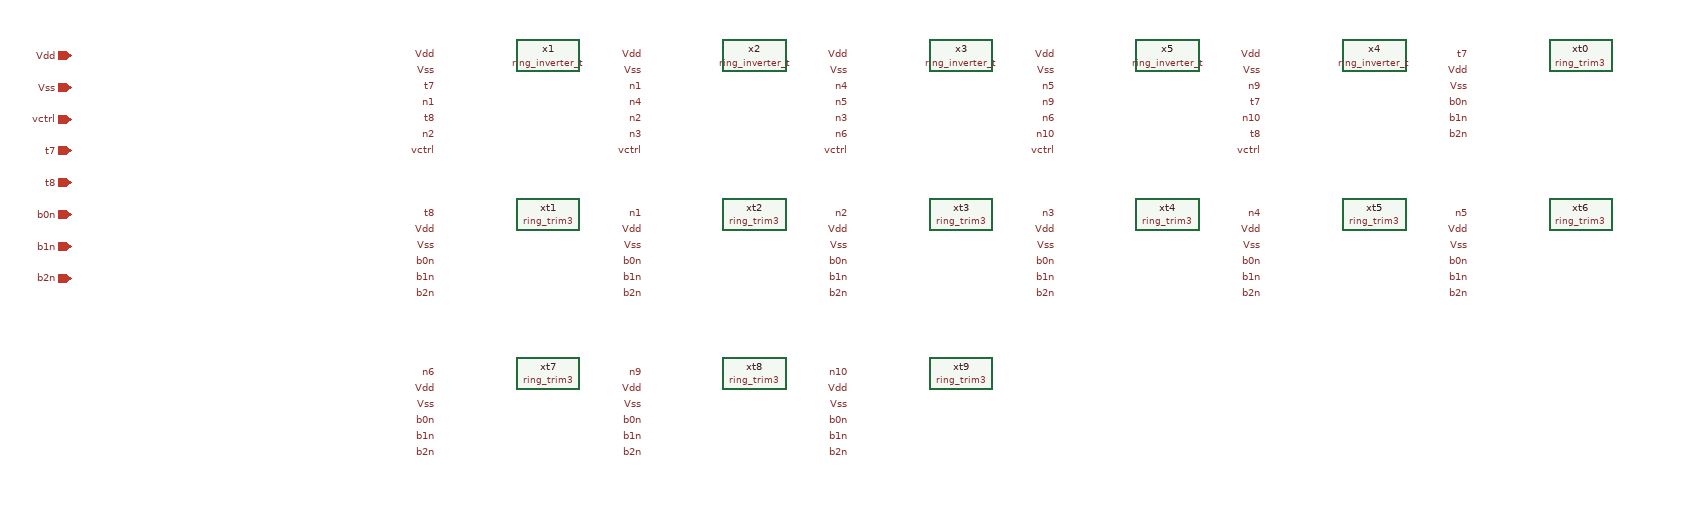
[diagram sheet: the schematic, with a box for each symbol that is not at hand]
v {xschem version=3.4.5 file_version=1.2}
G {}
K {}
V {}
S {}
E {}
C {devices/iopin.sym} -400 0 0 0 {name=p1 lab=Vdd}
C {devices/iopin.sym} -400 40 0 0 {name=p2 lab=Vss}
C {devices/iopin.sym} -400 80 0 0 {name=p3 lab=vctrl}
C {devices/iopin.sym} -400 120 0 0 {name=p4 lab=t7}
C {devices/iopin.sym} -400 160 0 0 {name=p5 lab=t8}
C {devices/iopin.sym} -400 200 0 0 {name=p6 lab=b0n}
C {devices/iopin.sym} -400 240 0 0 {name=p7 lab=b1n}
C {devices/iopin.sym} -400 280 0 0 {name=p8 lab=b2n}
C {devices/lab_pin.sym} 60 0 0 0 {name=l1 sig_type=std_logic lab=Vdd}
C {devices/lab_pin.sym} 60 20 0 0 {name=l2 sig_type=std_logic lab=Vss}
C {devices/lab_pin.sym} 60 40 0 0 {name=l3 sig_type=std_logic lab=t7}
C {devices/lab_pin.sym} 60 60 0 0 {name=l4 sig_type=std_logic lab=n1}
C {devices/lab_pin.sym} 60 80 0 0 {name=l5 sig_type=std_logic lab=t8}
C {devices/lab_pin.sym} 60 100 0 0 {name=l6 sig_type=std_logic lab=n2}
C {devices/lab_pin.sym} 60 120 0 0 {name=l7 sig_type=std_logic lab=vctrl}
C {cml/ring_inverter_t.sym} 200 0 0 0 {name=x1}
C {devices/lab_pin.sym} 320 0 0 0 {name=l8 sig_type=std_logic lab=Vdd}
C {devices/lab_pin.sym} 320 20 0 0 {name=l9 sig_type=std_logic lab=Vss}
C {devices/lab_pin.sym} 320 40 0 0 {name=l10 sig_type=std_logic lab=n1}
C {devices/lab_pin.sym} 320 60 0 0 {name=l11 sig_type=std_logic lab=n4}
C {devices/lab_pin.sym} 320 80 0 0 {name=l12 sig_type=std_logic lab=n2}
C {devices/lab_pin.sym} 320 100 0 0 {name=l13 sig_type=std_logic lab=n3}
C {devices/lab_pin.sym} 320 120 0 0 {name=l14 sig_type=std_logic lab=vctrl}
C {cml/ring_inverter_t.sym} 460 0 0 0 {name=x2}
C {devices/lab_pin.sym} 580 0 0 0 {name=l15 sig_type=std_logic lab=Vdd}
C {devices/lab_pin.sym} 580 20 0 0 {name=l16 sig_type=std_logic lab=Vss}
C {devices/lab_pin.sym} 580 40 0 0 {name=l17 sig_type=std_logic lab=n4}
C {devices/lab_pin.sym} 580 60 0 0 {name=l18 sig_type=std_logic lab=n5}
C {devices/lab_pin.sym} 580 80 0 0 {name=l19 sig_type=std_logic lab=n3}
C {devices/lab_pin.sym} 580 100 0 0 {name=l20 sig_type=std_logic lab=n6}
C {devices/lab_pin.sym} 580 120 0 0 {name=l21 sig_type=std_logic lab=vctrl}
C {cml/ring_inverter_t.sym} 720 0 0 0 {name=x3}
C {devices/lab_pin.sym} 840 0 0 0 {name=l22 sig_type=std_logic lab=Vdd}
C {devices/lab_pin.sym} 840 20 0 0 {name=l23 sig_type=std_logic lab=Vss}
C {devices/lab_pin.sym} 840 40 0 0 {name=l24 sig_type=std_logic lab=n5}
C {devices/lab_pin.sym} 840 60 0 0 {name=l25 sig_type=std_logic lab=n9}
C {devices/lab_pin.sym} 840 80 0 0 {name=l26 sig_type=std_logic lab=n6}
C {devices/lab_pin.sym} 840 100 0 0 {name=l27 sig_type=std_logic lab=n10}
C {devices/lab_pin.sym} 840 120 0 0 {name=l28 sig_type=std_logic lab=vctrl}
C {cml/ring_inverter_t.sym} 980 0 0 0 {name=x5}
C {devices/lab_pin.sym} 1100 0 0 0 {name=l29 sig_type=std_logic lab=Vdd}
C {devices/lab_pin.sym} 1100 20 0 0 {name=l30 sig_type=std_logic lab=Vss}
C {devices/lab_pin.sym} 1100 40 0 0 {name=l31 sig_type=std_logic lab=n9}
C {devices/lab_pin.sym} 1100 60 0 0 {name=l32 sig_type=std_logic lab=t7}
C {devices/lab_pin.sym} 1100 80 0 0 {name=l33 sig_type=std_logic lab=n10}
C {devices/lab_pin.sym} 1100 100 0 0 {name=l34 sig_type=std_logic lab=t8}
C {devices/lab_pin.sym} 1100 120 0 0 {name=l35 sig_type=std_logic lab=vctrl}
C {cml/ring_inverter_t.sym} 1240 0 0 0 {name=x4}
C {devices/lab_pin.sym} 1360 0 0 0 {name=l36 sig_type=std_logic lab=t7}
C {devices/lab_pin.sym} 1360 20 0 0 {name=l37 sig_type=std_logic lab=Vdd}
C {devices/lab_pin.sym} 1360 40 0 0 {name=l38 sig_type=std_logic lab=Vss}
C {devices/lab_pin.sym} 1360 60 0 0 {name=l39 sig_type=std_logic lab=b0n}
C {devices/lab_pin.sym} 1360 80 0 0 {name=l40 sig_type=std_logic lab=b1n}
C {devices/lab_pin.sym} 1360 100 0 0 {name=l41 sig_type=std_logic lab=b2n}
C {cml/ring_trim3.sym} 1500 0 0 0 {name=xt0}
C {devices/lab_pin.sym} 60 200 0 0 {name=l42 sig_type=std_logic lab=t8}
C {devices/lab_pin.sym} 60 220 0 0 {name=l43 sig_type=std_logic lab=Vdd}
C {devices/lab_pin.sym} 60 240 0 0 {name=l44 sig_type=std_logic lab=Vss}
C {devices/lab_pin.sym} 60 260 0 0 {name=l45 sig_type=std_logic lab=b0n}
C {devices/lab_pin.sym} 60 280 0 0 {name=l46 sig_type=std_logic lab=b1n}
C {devices/lab_pin.sym} 60 300 0 0 {name=l47 sig_type=std_logic lab=b2n}
C {cml/ring_trim3.sym} 200 200 0 0 {name=xt1}
C {devices/lab_pin.sym} 320 200 0 0 {name=l48 sig_type=std_logic lab=n1}
C {devices/lab_pin.sym} 320 220 0 0 {name=l49 sig_type=std_logic lab=Vdd}
C {devices/lab_pin.sym} 320 240 0 0 {name=l50 sig_type=std_logic lab=Vss}
C {devices/lab_pin.sym} 320 260 0 0 {name=l51 sig_type=std_logic lab=b0n}
C {devices/lab_pin.sym} 320 280 0 0 {name=l52 sig_type=std_logic lab=b1n}
C {devices/lab_pin.sym} 320 300 0 0 {name=l53 sig_type=std_logic lab=b2n}
C {cml/ring_trim3.sym} 460 200 0 0 {name=xt2}
C {devices/lab_pin.sym} 580 200 0 0 {name=l54 sig_type=std_logic lab=n2}
C {devices/lab_pin.sym} 580 220 0 0 {name=l55 sig_type=std_logic lab=Vdd}
C {devices/lab_pin.sym} 580 240 0 0 {name=l56 sig_type=std_logic lab=Vss}
C {devices/lab_pin.sym} 580 260 0 0 {name=l57 sig_type=std_logic lab=b0n}
C {devices/lab_pin.sym} 580 280 0 0 {name=l58 sig_type=std_logic lab=b1n}
C {devices/lab_pin.sym} 580 300 0 0 {name=l59 sig_type=std_logic lab=b2n}
C {cml/ring_trim3.sym} 720 200 0 0 {name=xt3}
C {devices/lab_pin.sym} 840 200 0 0 {name=l60 sig_type=std_logic lab=n3}
C {devices/lab_pin.sym} 840 220 0 0 {name=l61 sig_type=std_logic lab=Vdd}
C {devices/lab_pin.sym} 840 240 0 0 {name=l62 sig_type=std_logic lab=Vss}
C {devices/lab_pin.sym} 840 260 0 0 {name=l63 sig_type=std_logic lab=b0n}
C {devices/lab_pin.sym} 840 280 0 0 {name=l64 sig_type=std_logic lab=b1n}
C {devices/lab_pin.sym} 840 300 0 0 {name=l65 sig_type=std_logic lab=b2n}
C {cml/ring_trim3.sym} 980 200 0 0 {name=xt4}
C {devices/lab_pin.sym} 1100 200 0 0 {name=l66 sig_type=std_logic lab=n4}
C {devices/lab_pin.sym} 1100 220 0 0 {name=l67 sig_type=std_logic lab=Vdd}
C {devices/lab_pin.sym} 1100 240 0 0 {name=l68 sig_type=std_logic lab=Vss}
C {devices/lab_pin.sym} 1100 260 0 0 {name=l69 sig_type=std_logic lab=b0n}
C {devices/lab_pin.sym} 1100 280 0 0 {name=l70 sig_type=std_logic lab=b1n}
C {devices/lab_pin.sym} 1100 300 0 0 {name=l71 sig_type=std_logic lab=b2n}
C {cml/ring_trim3.sym} 1240 200 0 0 {name=xt5}
C {devices/lab_pin.sym} 1360 200 0 0 {name=l72 sig_type=std_logic lab=n5}
C {devices/lab_pin.sym} 1360 220 0 0 {name=l73 sig_type=std_logic lab=Vdd}
C {devices/lab_pin.sym} 1360 240 0 0 {name=l74 sig_type=std_logic lab=Vss}
C {devices/lab_pin.sym} 1360 260 0 0 {name=l75 sig_type=std_logic lab=b0n}
C {devices/lab_pin.sym} 1360 280 0 0 {name=l76 sig_type=std_logic lab=b1n}
C {devices/lab_pin.sym} 1360 300 0 0 {name=l77 sig_type=std_logic lab=b2n}
C {cml/ring_trim3.sym} 1500 200 0 0 {name=xt6}
C {devices/lab_pin.sym} 60 400 0 0 {name=l78 sig_type=std_logic lab=n6}
C {devices/lab_pin.sym} 60 420 0 0 {name=l79 sig_type=std_logic lab=Vdd}
C {devices/lab_pin.sym} 60 440 0 0 {name=l80 sig_type=std_logic lab=Vss}
C {devices/lab_pin.sym} 60 460 0 0 {name=l81 sig_type=std_logic lab=b0n}
C {devices/lab_pin.sym} 60 480 0 0 {name=l82 sig_type=std_logic lab=b1n}
C {devices/lab_pin.sym} 60 500 0 0 {name=l83 sig_type=std_logic lab=b2n}
C {cml/ring_trim3.sym} 200 400 0 0 {name=xt7}
C {devices/lab_pin.sym} 320 400 0 0 {name=l84 sig_type=std_logic lab=n9}
C {devices/lab_pin.sym} 320 420 0 0 {name=l85 sig_type=std_logic lab=Vdd}
C {devices/lab_pin.sym} 320 440 0 0 {name=l86 sig_type=std_logic lab=Vss}
C {devices/lab_pin.sym} 320 460 0 0 {name=l87 sig_type=std_logic lab=b0n}
C {devices/lab_pin.sym} 320 480 0 0 {name=l88 sig_type=std_logic lab=b1n}
C {devices/lab_pin.sym} 320 500 0 0 {name=l89 sig_type=std_logic lab=b2n}
C {cml/ring_trim3.sym} 460 400 0 0 {name=xt8}
C {devices/lab_pin.sym} 580 400 0 0 {name=l90 sig_type=std_logic lab=n10}
C {devices/lab_pin.sym} 580 420 0 0 {name=l91 sig_type=std_logic lab=Vdd}
C {devices/lab_pin.sym} 580 440 0 0 {name=l92 sig_type=std_logic lab=Vss}
C {devices/lab_pin.sym} 580 460 0 0 {name=l93 sig_type=std_logic lab=b0n}
C {devices/lab_pin.sym} 580 480 0 0 {name=l94 sig_type=std_logic lab=b1n}
C {devices/lab_pin.sym} 580 500 0 0 {name=l95 sig_type=std_logic lab=b2n}
C {cml/ring_trim3.sym} 720 400 0 0 {name=xt9}
